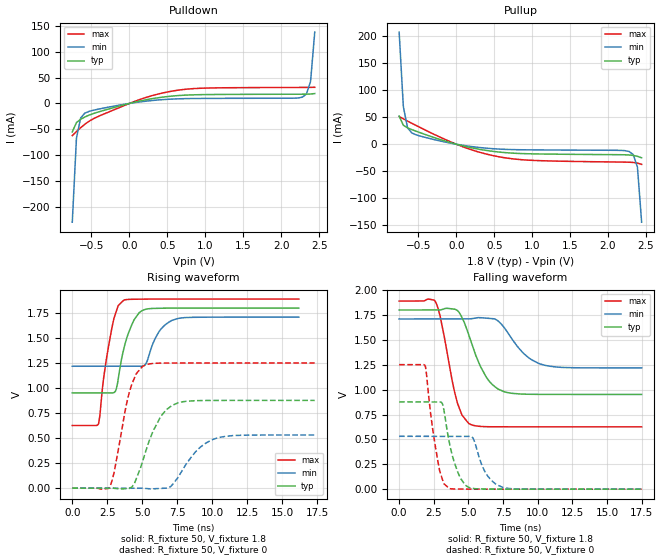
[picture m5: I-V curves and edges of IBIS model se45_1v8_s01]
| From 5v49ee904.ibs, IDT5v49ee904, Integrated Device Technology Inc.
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[Model]   se45_1v8_s01
Model_type   Output
Polarity   Non-Inverting
|   typ   min   max
C_comp   2pF   1.5pF   2.5pF
Vmeas = 0.9V
Rref = 50
Cref = 0
Vref = 0.9V
|   typ   min   max
[Voltage range]   1.8V   1.71V   1.89V
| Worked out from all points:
|   slope of the pulldown table from 0 to 0.27 V, typ, clamps not added: 32 ohm
|   slope of the pullup table from 0 to 0.27 V, typ, clamps not added: 31.6 ohm
|   rising waveform, R_fixture 50, V_fixture 1.8: 20-80 % time 925ps typ, 1.02ns min, 813ps max; typ from 0.952 V to 1.8 V
|   falling waveform, R_fixture 50, V_fixture 1.8: 20-80 % time 1.49ns typ, 1.74ns min, 1.08ns max; typ from 1.8 V to 0.952 V
|   rising waveform, R_fixture 50, V_fixture 0: 20-80 % time 1.46ns typ, 1.74ns min, 1.06ns max; typ from 0 V to 0.877 V
|   falling waveform, R_fixture 50, V_fixture 0: 20-80 % time 881ps typ, 983ps min, 753ps max; typ from 0.877 V to 0 V
[Pulldown]
|Voltage   I (typ)   I (min)   I (max)
|Note, modeling breaks down at 250mA and above.  This is well beyond the functional   |
|operating range of the device.  Should this scenario occur, catastrophic failure and   |
|possible damage to the device and/or board is of higher concern than the I-V curve   |
|behavior.  The IBIS checker will flag currents in excess of 10A with warnings.  Lines   |
|with currents in excess of 0.35 A have been commented out.  The points still remain|
|available to the user if the user desires to use them.   |
|-1.80000e+00   -2.52572e+01   -2.08112e+01   -3.26463e+01
|-1.74490e+00   -2.36799e+01   -1.95979e+01   -3.04476e+01
|-1.68980e+00   -2.21059e+01   -1.83872e+01   -2.82531e+01
|-1.63469e+00   -2.05356e+01   -1.71794e+01   -2.60635e+01
|-1.57959e+00   -1.89696e+01   -1.59750e+01   -2.38796e+01
|-1.52449e+00   -1.74087e+01   -1.47744e+01   -2.17024e+01
|-1.46939e+00   -1.58536e+01   -1.35783e+01   -1.95332e+01
|-1.41429e+00   -1.43055e+01   -1.23874e+01   -1.73739e+01
|-1.35918e+00   -1.27659e+01   -1.12027e+01   -1.52269e+01
|-1.30408e+00   -1.12368e+01   -1.00254e+01   -1.30956e+01
|-1.24898e+00   -9.72098e+00   -8.85722e+00   -1.09851e+01
|-1.19388e+00   -8.22246e+00   -7.70043e+00   -8.90351e+00
|-1.13878e+00   -6.74727e+00   -6.55830e+00   -6.86403e+00
|-1.08367e+00   -5.30512e+00   -5.43552e+00   -4.89135e+00
|-1.02857e+00   -3.91270e+00   -4.33946e+00   -3.03736e+00
|-9.73469e-01   -2.60169e+00   -3.28214e+00   -1.43100e+00
|-9.18367e-01   -1.43880e+00   -2.28475e+00   -3.94093e-01
|-8.63265e-01   -5.66865e-01   -1.38741e+00   -1.06939e-01
|-8.08163e-01   -1.52138e-01   -6.66903e-01   -7.19895e-02
-753.1mV  -54.82mA   -228.9mA   -62.01mA
-698mV    -36.89mA   -66.92mA   -54.09mA
-642.9mV  -30.52mA   -28.08mA   -46.79mA
-587.8mV  -26.13mA   -18.74mA   -40.17mA
-422.4mV  -17.04mA   -11.39mA   -25.78mA
73.47mV   2.606mA    1.636mA    4.206mA
569.4mV   14.28mA    8.482mA    23.96mA
1.01V     17.09mA    9.709mA    29.63mA
2.278V    17.85mA    12.06mA    30.89mA
2.333V    17.94mA    17.98mA    30.92mA
2.388V    18.19mA    42.4mA     30.98mA
2.443V    19.06mA    137.5mA    31.13mA
| 2.49796e+00   2.27208e-02   3.74787e-01   3.15041e-02
| 2.55306e+00   4.08756e-02   7.43068e-01   3.22551e-02
| 2.60816e+00   1.37566e-01   1.19023e+00   3.34916e-02
| 2.66327e+00   4.37820e-01   1.68221e+00   3.56718e-02
| 2.71837e+00   9.27501e-01   2.20139e+00   4.47214e-02
| 2.77347e+00   1.51885e+00   2.73835e+00   1.23384e-01
| 2.82857e+00   2.16314e+00   3.28769e+00   4.92594e-01
| 2.88367e+00   2.83803e+00   3.84607e+00   1.15125e+00
| 2.93878e+00   3.53242e+00   4.41129e+00   1.94102e+00
| 2.99388e+00   4.24015e+00   4.98190e+00   2.79125e+00
| 3.04898e+00   4.95754e+00   5.55682e+00   3.67438e+00
| 3.10408e+00   5.68219e+00   6.13525e+00   4.57781e+00
| 3.15918e+00   6.41253e+00   6.71663e+00   5.49491e+00
| 3.21429e+00   7.14740e+00   7.30048e+00   6.42176e+00
| 3.26939e+00   7.88598e+00   7.88646e+00   7.35591e+00
| 3.32449e+00   8.62763e+00   8.47428e+00   8.29574e+00
| 3.37959e+00   9.37188e+00   9.06370e+00   9.24008e+00
| 3.43469e+00   1.01184e+01   9.65453e+00   1.01881e+01
| 3.48980e+00   1.08667e+01   1.02466e+01   1.11392e+01
| 3.54490e+00   1.16168e+01   1.08398e+01   1.20928e+01
| 3.60000e+00   1.23684e+01   1.14340e+01   1.30487e+01
[Pullup]
|Voltage   I (typ)   I (min)   I (max)
|Note, modeling breaks down at 250mA and above.  This is well beyond the functional   |
|operating range of the device.  Should this scenario occur, catastrophic failure and   |
|possible damage to the device and/or board is of higher concern than the I-V curve   |
|behavior.  The IBIS checker will flag currents in excess of 10A with warnings.  Lines   |
|with currents in excess of 0.35 A have been commented out.  The points still remain|
|available to the user if the user desires to use them.   |
|-1.80000e+00   1.23492e+01   1.04530e+01   1.45809e+01
|-1.74490e+00   1.15979e+01   9.86061e+00   1.36224e+01
|-1.68980e+00   1.08480e+01   9.26940e+00   1.26656e+01
|-1.63469e+00   1.00998e+01   8.67956e+00   1.17108e+01
|-1.57959e+00   9.35349e+00   8.09124e+00   1.07584e+01
|-1.52449e+00   8.60944e+00   7.50468e+00   9.80872e+00
|-1.46939e+00   7.86800e+00   6.92013e+00   8.86233e+00
|-1.41429e+00   7.12967e+00   6.33794e+00   7.91994e+00
|-1.35918e+00   6.39506e+00   5.75851e+00   6.98248e+00
|-1.30408e+00   5.66501e+00   5.18238e+00   6.05131e+00
|-1.24898e+00   4.94068e+00   4.61027e+00   5.12833e+00
|-1.19388e+00   4.22372e+00   4.04313e+00   4.21650e+00
|-1.13878e+00   3.51650e+00   3.48228e+00   3.32063e+00
|-1.08367e+00   2.82280e+00   2.92962e+00   2.44927e+00
|-1.02857e+00   2.14888e+00   2.38803e+00   1.61954e+00
|-9.73469e-01   1.50615e+00   1.86206e+00   8.71510e-01
|-9.18367e-01   9.17564e-01   1.35944e+00   3.11233e-01
|-8.63265e-01   4.33414e-01   8.94316e-01   8.94593e-02
|-8.08163e-01   1.42396e-01   4.94089e-01   5.74619e-02
-753.1mV  52mA       207.1mA    51.2mA
-698mV    35.06mA    69.7mA     46.91mA
-642.9mV  30.25mA    30.46mA    42.81mA
-587.8mV  27.07mA    20.93mA    38.78mA
-312.2mV  13.24mA    9.215mA    19.54mA
73.47mV   -2.62mA    -1.732mA   -4.049mA
569.4mV   -14.56mA   -9.029mA   -23.39mA
1.065V    -17.95mA   -10.52mA   -30.19mA
2.278V    -19.91mA   -13.47mA   -33.25mA
2.333V    -20.75mA   -19.16mA   -33.68mA
2.388V    -22.37mA   -42.35mA   -34.85mA
2.443V    -25.08mA   -144mA     -37.25mA
| 2.49796e+00   -3.03122e-02   -4.72515e-01   -4.09753e-02
| 2.55306e+00   -4.85503e-02   -1.10341e+00   -4.57713e-02
| 2.60816e+00   -1.49867e-01   -1.94886e+00   -5.14012e-02
| 2.66327e+00   -5.72739e-01   -2.91646e+00   -5.79887e-02
| 2.71837e+00   -1.45030e+00   -3.95533e+00   -7.00790e-02
| 2.77347e+00   -2.61576e+00   -5.03908e+00   -1.50146e-01
| 2.82857e+00   -3.92793e+00   -6.15313e+00   -6.90731e-01
| 2.88367e+00   -5.32086e+00   -7.28879e+00   -1.99805e+00
| 2.93878e+00   -6.76320e+00   -8.44055e+00   -3.72340e+00
| 2.99388e+00   -8.23838e+00   -9.60470e+00   -5.63149e+00
| 3.04898e+00   -9.73678e+00   -1.07787e+01   -7.63318e+00
| 3.10408e+00   -1.12524e+01   -1.19607e+01   -9.69020e+00
| 3.15918e+00   -1.27812e+01   -1.31493e+01   -1.17833e+01
| 3.21429e+00   -1.43206e+01   -1.43434e+01   -1.39018e+01
| 3.26939e+00   -1.58683e+01   -1.55422e+01   -1.60388e+01
| 3.32449e+00   -1.74231e+01   -1.67451e+01   -1.81901e+01
| 3.37959e+00   -1.89838e+01   -1.79514e+01   -2.03526e+01
| 3.43469e+00   -2.05494e+01   -1.91609e+01   -2.25242e+01
| 3.48980e+00   -2.21193e+01   -2.03730e+01   -2.47033e+01
| 3.54490e+00   -2.36930e+01   -2.15876e+01   -2.68887e+01
| 3.60000e+00   -2.52699e+01   -2.28044e+01   -2.90795e+01
[Ramp]
|   typ   min   max
dV/dt_r   0.509/0.924n   0.295/1.02n   0.758/0.812n
dV/dt_f   0.519/1.506n   0.303/1.771n   0.77/1.093n
R_load =   50.0000
[Rising Waveform]
R_fixture = 50
V_fixture = 1.8   |Vcc_typ
V_fixture_min = 1.71 |Vcc_min
V_fixture_max = 1.89 |Vcc_max
C_fixture = 0.0p
| Time   typ   min   max
0s        951.9mV    1.218V     626.3mV
1.883ns   951.9mV    1.218V     645.4mV
2.302ns   951.9mV    1.218V     1.162V
2.937ns   953.1mV    1.218V     1.674V
3.715ns   1.414V     1.218V     1.881V
4.795ns   1.756V     1.218V     1.889V
5.25ns    1.788V     1.24V      1.89V
6.288ns   1.798V     1.582V     1.89V
7.5ns     1.8V       1.695V     1.89V
16.18ns   1.8V       1.71V      1.89V
[Falling Waveform]
R_fixture = 50
V_fixture = 1.8   |Vcc_typ
V_fixture_min = 1.71 |Vcc_min
V_fixture_max = 1.89 |Vcc_max
C_fixture = 0.0p
| Time   typ   min   max
0s        1.8V       1.71V      1.89V
2.605ns   1.8V       1.71V      1.887V
2.953ns   1.801V     1.71V      1.741V
4.213ns   1.794V     1.71V      862mV
5.1ns     1.518V     1.711V     654.3mV
6.25ns    1.134V     1.718V     627.6mV
7.524ns   981.5mV    1.634V     626.6mV
8.964ns   954.8mV    1.366V     626.5mV
10.28ns   952.2mV    1.253V     626.4mV
17.5ns    951.9mV    1.218V     626.4mV
[Rising Waveform]
R_fixture = 50
V_fixture = 0
C_fixture = 0.0p
| Time   typ   min   max
0s        62.71nV    55.96nV    63.02nV
2.652ns   23.86uV    55.56nV    7.772mV
2.982ns   -1.194mV   60nV       152.9mV
4.052ns   -3.426mV   -508.8nV   944.9mV
5.113ns   310.3mV    -1.479mV   1.224V
6.262ns   702.1mV    -3.32mV    1.25V
7.521ns   851.4mV    100.7mV    1.251V
8.858ns   874.6mV    371.3mV    1.251V
10.25ns   876.8mV    497.4mV    1.251V
17.32ns   876.9mV    531.2mV    1.251V
[Falling Waveform]
R_fixture = 50
V_fixture = 0
C_fixture = 0.0p
| Time   typ   min   max
0s        876.9mV    531.2mV    1.251V
1.901ns   876.9mV    531.2mV    1.23V
2.929ns   877.2mV    531.2mV    181.6mV
3.174ns   836.2mV    531.2mV    76.85mV
3.63ns    461.7mV    531.2mV    5.094mV
4.414ns   112.2mV    531.2mV    913.8uV
5.191ns   10.96mV    528.1mV    354.6uV
6.285ns   1.005mV    154mV      108.8uV
7.5ns     274.3uV    16.57mV    78.26uV
17.5ns    44.15uV    87.84uV    23.35uV
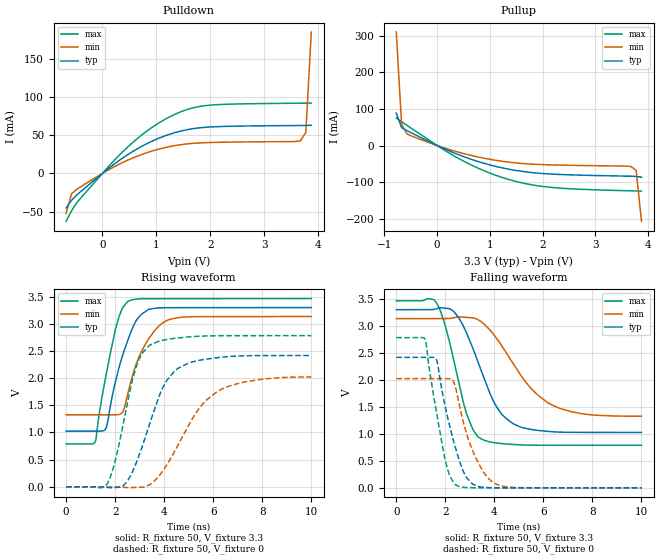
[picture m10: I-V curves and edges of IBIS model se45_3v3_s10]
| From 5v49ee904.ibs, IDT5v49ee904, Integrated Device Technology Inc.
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[Model]   se45_3v3_s10
Model_type   Output
Polarity   Non-Inverting
|   typ   min   max
C_comp   2pF   1.5pF   2.5pF
Vmeas = 1.65V
Rref = 50
Cref = 0
Vref = 1.65V
|   typ   min   max
[Voltage range]   3.3V   3.135V   3.465V
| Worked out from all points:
|   slope of the pulldown table from 0 to 0.495 V, typ, clamps not added: 19.3 ohm
|   slope of the pullup table from 0 to 0.495 V, typ, clamps not added: 16.5 ohm
|   rising waveform, R_fixture 50, V_fixture 3.3: 20-80 % time 835ps typ, 942ps min, 686ps max; typ from 1.03 V to 3.3 V
|   falling waveform, R_fixture 50, V_fixture 3.3: 20-80 % time 1.23ns typ, 1.78ns min, 866ps max; typ from 3.3 V to 1.03 V
|   rising waveform, R_fixture 50, V_fixture 0: 20-80 % time 1.18ns typ, 1.67ns min, 832ps max; typ from 0 V to 2.42 V
|   falling waveform, R_fixture 50, V_fixture 0: 20-80 % time 776ps typ, 881ps min, 637ps max; typ from 2.42 V to 0 V
[Pulldown]
|Voltage   I (typ)   I (min)   I (max)
|Note, modeling breaks down at 250mA and above.  This is well beyond the functional   |
|operating range of the device.  Should this scenario occur, catastrophic failure and   |
|possible damage to the device and/or board is of higher concern than the I-V curve   |
|behavior.  The IBIS checker will flag currents in excess of 10A with warnings.  Lines   |
|with currents in excess of 0.35 A have been commented out.  The points still remain|
|available to the user if the user desires to use them.   |
|-3.30000e+00   -6.87686e+01   -5.43171e+01   -9.32008e+01
|-3.19898e+00   -6.58203e+01   -5.20452e+01   -8.91014e+01
|-3.09796e+00   -6.28735e+01   -4.97746e+01   -8.50038e+01
|-2.99694e+00   -5.99283e+01   -4.75054e+01   -8.09081e+01
|-2.89592e+00   -5.69850e+01   -4.52379e+01   -7.68145e+01
|-2.79490e+00   -5.40436e+01   -4.29721e+01   -7.27232e+01
|-2.69388e+00   -5.11045e+01   -4.07082e+01   -6.86345e+01
|-2.59286e+00   -4.81679e+01   -3.84464e+01   -6.45487e+01
|-2.49184e+00   -4.52341e+01   -3.61871e+01   -6.04662e+01
|-2.39082e+00   -4.23034e+01   -3.39304e+01   -5.63874e+01
|-2.28980e+00   -3.93763e+01   -3.16768e+01   -5.23129e+01
|-2.18878e+00   -3.64533e+01   -2.94267e+01   -4.82433e+01
|-2.08776e+00   -3.35351e+01   -2.71807e+01   -4.41794e+01
|-1.98673e+00   -3.06226e+01   -2.49393e+01   -4.01225e+01
|-1.88571e+00   -2.77168e+01   -2.27035e+01   -3.60739e+01
|-1.78469e+00   -2.48192e+01   -2.04743e+01   -3.20355e+01
|-1.68367e+00   -2.19317e+01   -1.82533e+01   -2.80101e+01
|-1.58265e+00   -1.90571e+01   -1.60423e+01   -2.40013e+01
|-1.48163e+00   -1.61992e+01   -1.38443e+01   -2.00151e+01
|-1.38061e+00   -1.33643e+01   -1.16633e+01   -1.60610e+01
|-1.27959e+00   -1.05622e+01   -9.50583e+00   -1.21557e+01
|-1.17857e+00   -7.81131e+00   -7.38261e+00   -8.33341e+00
|-1.07755e+00   -5.14939e+00   -5.31366e+00   -4.68044e+00
|-9.76531e-01   -2.67462e+00   -3.34162e+00   -1.51483e+00
|-8.75510e-01   -7.31794e-01   -1.57851e+00   -1.44651e-01
|-7.74490e-01   -8.69816e-02   -3.68375e-01   -7.86452e-02
-673.5mV  -45.24mA   -52.43mA   -62.63mA
-572.4mV  -35.28mA   -26.51mA   -48.86mA
-471.4mV  -27.99mA   -20.59mA   -38.06mA
134.7mV   7.697mA    5.495mA    10.74mA
437.8mV   23.12mA    16.34mA    32.53mA
841.8mV   39.56mA    27.55mA    56.35mA
1.246V    51.27mA    35.11mA    74.04mA
1.65V     58.26mA    39.16mA    85.27mA
1.953V    60.57mA    40.35mA    89.06mA
3.67V     62.68mA    42.56mA    91.89mA
3.771V    62.76mA    53.73mA    91.95mA
3.872V    63.02mA    185mA      92.02mA
| 3.97347e+00   6.55596e-02   7.41798e-01   9.21553e-02
| 4.07449e+00   1.08647e-01   1.58880e+00   9.27153e-02
| 4.17551e+00   5.80299e-01   2.54532e+00   9.46081e-02
| 4.27653e+00   1.59953e+00   3.55180e+00   1.01817e-01
| 4.37755e+00   2.80777e+00   4.58590e+00   3.34477e-01
| 4.47857e+00   4.08831e+00   5.63734e+00   1.48889e+00
| 4.57959e+00   5.40528e+00   6.70059e+00   3.02324e+00
| 4.68061e+00   6.74390e+00   7.77238e+00   4.66566e+00
| 4.78163e+00   8.09679e+00   8.85061e+00   6.35541e+00
| 4.88265e+00   9.45977e+00   9.93391e+00   8.07133e+00
| 4.98367e+00   1.08302e+01   1.10213e+01   9.80380e+00
| 5.08469e+00   1.22065e+01   1.21119e+01   1.15477e+01
| 5.18571e+00   1.35874e+01   1.32054e+01   1.32998e+01
| 5.28673e+00   1.49721e+01   1.43012e+01   1.50583e+01
| 5.38776e+00   1.63599e+01   1.53991e+01   1.68219e+01
| 5.48878e+00   1.77503e+01   1.64987e+01   1.85895e+01
| 5.58980e+00   1.91430e+01   1.75998e+01   2.03604e+01
| 5.69082e+00   2.05377e+01   1.87024e+01   2.21342e+01
| 5.79184e+00   2.19342e+01   1.98062e+01   2.39105e+01
| 5.89286e+00   2.33322e+01   2.09111e+01   2.56888e+01
| 5.99388e+00   2.47315e+01   2.20170e+01   2.74690e+01
| 6.09490e+00   2.61321e+01   2.31238e+01   2.92508e+01
| 6.19592e+00   2.75338e+01   2.42314e+01   3.10341e+01
| 6.29694e+00   2.89366e+01   2.53398e+01   3.28186e+01
| 6.39796e+00   3.03402e+01   2.64489e+01   3.46043e+01
| 6.49898e+00   3.17447e+01   2.75587e+01   3.63909e+01
| 6.60000e+00   3.31499e+01   2.86691e+01   3.81786e+01
[Pullup]
|Voltage   I (typ)   I (min)   I (max)
|Note, modeling breaks down at 250mA and above.  This is well beyond the functional   |
|operating range of the device.  Should this scenario occur, catastrophic failure and   |
|possible damage to the device and/or board is of higher concern than the I-V curve   |
|behavior.  The IBIS checker will flag currents in excess of 10A with warnings.  Lines   |
|with currents in excess of 0.35 A have been commented out.  The points still remain|
|available to the user if the user desires to use them.   |
|-3.30000e+00   3.30685e+01   2.68041e+01   4.09731e+01
|-3.19898e+00   3.16649e+01   2.56956e+01   3.91868e+01
|-3.09796e+00   3.02620e+01   2.45879e+01   3.74012e+01
|-2.99694e+00   2.88598e+01   2.34808e+01   3.56164e+01
|-2.89592e+00   2.74585e+01   2.23744e+01   3.38325e+01
|-2.79490e+00   2.60582e+01   2.12689e+01   3.20497e+01
|-2.69388e+00   2.46589e+01   2.01643e+01   3.02679e+01
|-2.59286e+00   2.32607e+01   1.90607e+01   2.84873e+01
|-2.49184e+00   2.18638e+01   1.79583e+01   2.67082e+01
|-2.39082e+00   2.04684e+01   1.68571e+01   2.49306e+01
|-2.28980e+00   1.90746e+01   1.57574e+01   2.31549e+01
|-2.18878e+00   1.76827e+01   1.46593e+01   2.13812e+01
|-2.08776e+00   1.62931e+01   1.35631e+01   1.96100e+01
|-1.98673e+00   1.49060e+01   1.24691e+01   1.78417e+01
|-1.88571e+00   1.35221e+01   1.13777e+01   1.60769e+01
|-1.78469e+00   1.21418e+01   1.02894e+01   1.43164e+01
|-1.68367e+00   1.07662e+01   9.20489e+00   1.25612e+01
|-1.58265e+00   9.39630e+00   8.12499e+00   1.08130e+01
|-1.48163e+00   8.03397e+00   7.05098e+00   9.07412e+00
|-1.38061e+00   6.68178e+00   5.98471e+00   7.34826e+00
|-1.27959e+00   5.34400e+00   4.92891e+00   5.64201e+00
|-1.17857e+00   4.02815e+00   3.88819e+00   3.96831e+00
|-1.07755e+00   2.74939e+00   2.87074e+00   2.35829e+00
|-9.76531e-01   1.54478e+00   1.89336e+00   9.17339e-01
|-8.75510e-01   5.36288e-01   9.97523e-01   1.33296e-01
-774.5mV  88.48mA    310mA      75.29mA
-673.5mV  49mA       58.32mA    64.98mA
-572.4mV  40.75mA    31.76mA    55.15mA
-67.35mV  4.603mA    3.395mA    6.411mA
437.8mV   -26.87mA   -19.51mA   -37.82mA
841.8mV   -46.61mA   -33.39mA   -66.08mA
1.347V    -64.42mA   -45.25mA   -92.37mA
1.751V    -73.29mA   -50.54mA   -106.3mA
2.155V    -77.96mA   -52.94mA   -114.3mA
3.67V     -83.83mA   -57.37mA   -123.8mA
3.771V    -84.41mA   -67.8mA    -124.1mA
3.872V    -86.53mA   -207mA     -124.6mA
| 3.97347e+00   -9.23636e-02   -1.08741e+00   -1.26631e-01
| 4.07449e+00   -1.35075e-01   -2.71250e+00   -1.32720e-01
| 4.17551e+00   -7.98376e-01   -4.62912e+00   -1.42442e-01
| 4.27653e+00   -2.75140e+00   -6.66999e+00   -1.56925e-01
| 4.37755e+00   -5.22889e+00   -8.77650e+00   -4.29683e-01
| 4.47857e+00   -7.89161e+00   -1.09230e+01   -2.68260e+00
| 4.57959e+00   -1.06427e+01   -1.30961e+01   -6.10746e+00
| 4.68061e+00   -1.34446e+01   -1.52882e+01   -9.84047e+00
| 4.78163e+00   -1.62792e+01   -1.74945e+01   -1.36990e+01
| 4.88265e+00   -1.91366e+01   -1.97119e+01   -1.76242e+01
| 4.98367e+00   -2.20108e+01   -2.19380e+01   -2.15907e+01
| 5.08469e+00   -2.48978e+01   -2.41712e+01   -2.55849e+01
| 5.18571e+00   -2.77948e+01   -2.64103e+01   -2.95993e+01
| 5.28673e+00   -3.07000e+01   -2.86544e+01   -3.36287e+01
| 5.38776e+00   -3.36120e+01   -3.09027e+01   -3.76698e+01
| 5.48878e+00   -3.65296e+01   -3.31547e+01   -4.17205e+01
| 5.58980e+00   -3.94519e+01   -3.54100e+01   -4.57788e+01
| 5.69082e+00   -4.23784e+01   -3.76680e+01   -4.98436e+01
| 5.79184e+00   -4.53085e+01   -3.99286e+01   -5.39138e+01
| 5.89286e+00   -4.82418e+01   -4.21914e+01   -5.79887e+01
| 5.99388e+00   -5.11778e+01   -4.44562e+01   -6.20677e+01
| 6.09490e+00   -5.41163e+01   -4.67228e+01   -6.61502e+01
| 6.19592e+00   -5.70570e+01   -4.89910e+01   -7.02359e+01
| 6.29694e+00   -5.99998e+01   -5.12608e+01   -7.43243e+01
| 6.39796e+00   -6.29443e+01   -5.35319e+01   -7.84152e+01
| 6.49898e+00   -6.58905e+01   -5.58042e+01   -8.25083e+01
| 6.60000e+00   -6.88383e+01   -5.80778e+01   -8.66035e+01
[Ramp]
|   typ   min   max
dV/dt_r   1.364/0.834n   1.085/0.942n   1.606/0.686n
dV/dt_f   1.385/1.25n  1.104/1.804n   1.63/0.878n
R_load =   50.0000
[Rising Waveform]
R_fixture = 50
V_fixture = 3.3   |Vcc_typ
V_fixture_min = 3.135 |Vcc_min
V_fixture_max = 3.465 |Vcc_max
C_fixture = 0.0p
| Time   typ   min   max
0s        1.026V     1.326V     788.2mV
1.184ns   1.026V     1.326V     827.4mV
1.633ns   1.085V     1.326V     2.063V
2.159ns   2.197V     1.331V     3.134V
2.324ns   2.446V     1.387V     3.307V
2.5ns     2.68V      1.683V     3.406V
2.837ns   3.043V     2.231V     3.453V
3.257ns   3.234V     2.647V     3.463V
4.149ns   3.297V     3.07V      3.464V
10ns      3.3V       3.135V     3.465V
[Falling Waveform]
R_fixture = 50
V_fixture = 3.3   |Vcc_typ
V_fixture_min = 3.135 |Vcc_min
V_fixture_max = 3.465 |Vcc_max
C_fixture = 0.0p
| Time   typ   min   max
0s        3.3V       3.135V     3.465V
1.627ns   3.316V     3.135V     3.436V
2.022ns   3.326V     3.135V     2.964V
2.5ns     3.18V      3.166V     2.05V
2.859ns   2.877V     3.158V     1.38V
3.459ns   2.178V     3.079V     908.3mV
4.314ns   1.355V     2.622V     818.9mV
5.405ns   1.09V      1.888V     791.5mV
6.17ns    1.045V     1.58V      788.5mV
10ns      1.026V     1.327V     788.3mV
[Rising Waveform]
R_fixture = 50
V_fixture = 0
C_fixture = 0.0p
| Time   typ   min   max
0s        124.7nV    139.7nV    109.3nV
1.692ns   -11.97mV   -267.1nV   65.86mV
2.517ns   120.7mV    -15.78mV   1.581V
2.976ns   581.3mV    -8.809mV   2.352V
3.412ns   1.167V     39.45mV    2.61V
3.971ns   1.85V      309mV      2.701V
4.551ns   2.179V     755.7mV    2.74V
5.349ns   2.321V     1.395V     2.77V
6.25ns    2.382V     1.778V     2.783V
10ns      2.417V     2.023V     2.783V
[Falling Waveform]
R_fixture = 50
V_fixture = 0
C_fixture = 0.0p
| Time   typ   min   max
0s        2.417V     2.024V     2.783V
1.179ns   2.417V     2.024V     2.751V
1.658ns   2.358V     2.024V     1.352V
2.071ns   1.348V     2.024V     373.6mV
2.394ns   773.9mV    1.903V     63.33mV
2.766ns   273.4mV    1.163V     8.781mV
3.187ns   55.45mV    606.1mV    1.458mV
3.574ns   10.23mV    281.8mV    986.6uV
4.049ns   1.9mV      74.21mV    790uV
10ns      54.4uV     94.26uV    31.48uV
